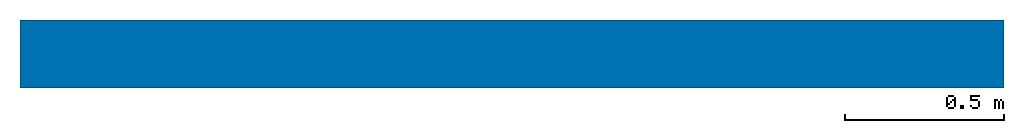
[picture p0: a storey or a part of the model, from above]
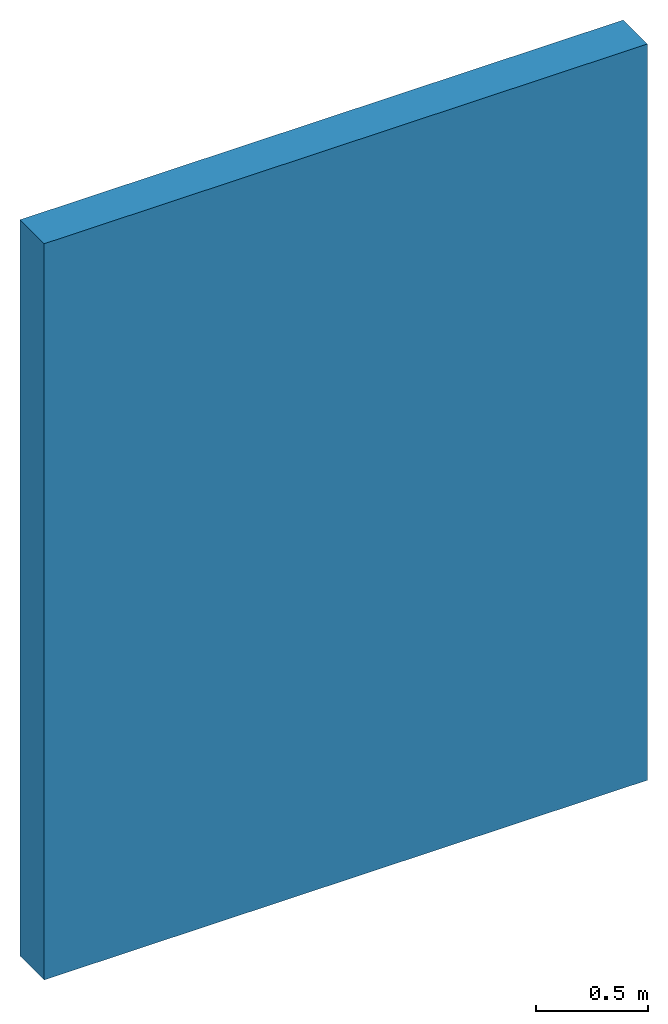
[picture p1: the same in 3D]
Properties of the parts of a building model (IFC2X3)

# File
Description: ViewDefinition [CoordinationView_V2.0], RevitIdentifiers [ContentGUID: 89c20d6a-6054-42c9-8fd4-a9e20ad917b2, VersionGUID: 0c752d05-d22e-4926-bb76-15eda85cbcbe, NumberOfSaves: 0], CoordinateReference [CoordinateBase: Shared Coordinates, ProjectSite: Default Site]
File name: Project1.ifc
Time: 2025-01-31T18:48:34-05:00
Written by: ODA SDAI 24.12
Made in: Autodesk Revit 25.4.0.32 (ENG) - IFC 25.4.0.32

# IfcProject, Project Number
LongName: Project Name; Phase: Project Status

# IfcSite, Default
RefLatitude: 51, 30, 23, 112487; RefLongitude: 0, -7, -37, -956022; RefElevation: 0 mm

# IfcBuilding
Pset_BuildingCommon - NumberOfStoreys: 1

# IfcBuildingStorey: Level:Circle Head - Project Datum (2)
Pset_AirSideSystemInformation - sets with these values: 2
Name | LongName = Name | Elevation (mm)
Level 0 | Level 0 | 0
Level 1 | Level 1 | 4000

# IfcWallStandardCase: Basic Wall:Wall-Ext_215Bwk, Basic Wall:Wall-Ext_215Bwk:323437
In: Level 0
Type - PredefinedType: STANDARD; Material: Brick, Common 215 mm
Type - Pset_WallCommon - ThermalTransmittance: 2.51163 kg/K/s3
Pset_QuantityTakeOff - Reference: Wall-Ext_215Bwk; sets with these values: 2
Pset_WallCommon - Reference: Wall-Ext_215Bwk; IsExternal: yes; ExtendToStructure: no; LoadBearing: no
ConstructionData - Completed: yes
